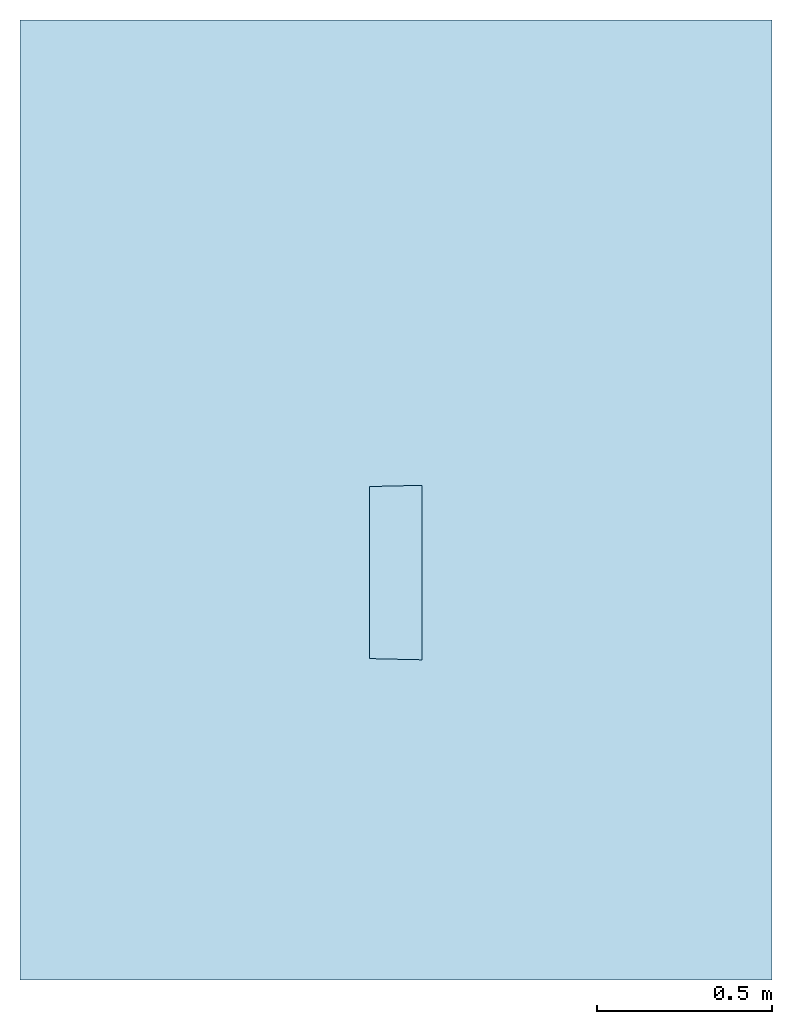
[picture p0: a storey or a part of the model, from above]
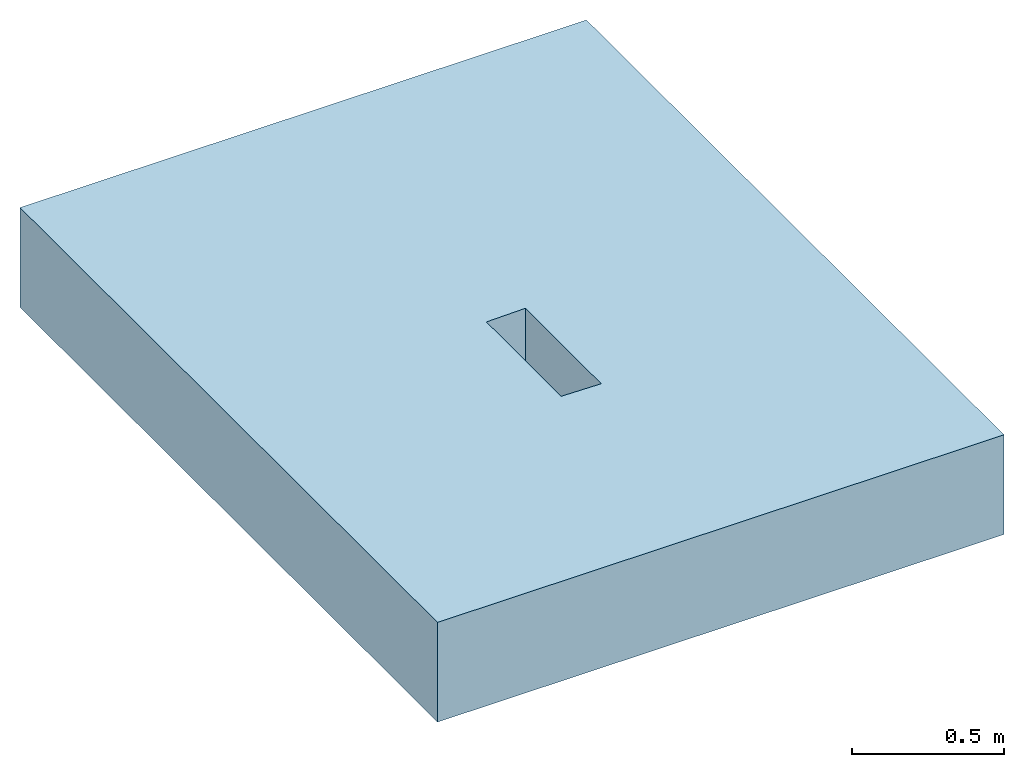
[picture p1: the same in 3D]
Properties of the parts of a building model (IFC2X3)

# File
Description: ViewDefinition [CoordinationView]
File name: 4936 - 25-11m external mitre.ifc
Time: 2013-09-18T16:24:00
Written by: Autodesk Revit 2013
Made in: 20120221_2030(x64)

# IfcProject, Project Number
LongName: Project Name; Phase: Project Status

# IfcSite, Default
RefLatitude: 42, 21, 30, 344238; RefLongitude: -71, -3, -35, -194702; RefElevation: 0 mm

# IfcBuilding
Pset_BuildingCommon - NumberOfStoreys: 2
Other - Project Name: Project Name; Client Name: Owner; Project Number: Project Number; Project Address: Enter address here; Project Status: Project Status; Project Issue Date: Issue Date

# IfcBuildingStorey (2)
Constraints - Elevation Base: 0
Graphics - Symbol at End 2 Default: yes; Color: 0; Line Weight: 1; Line Pattern: Center; Symbol at End 1 Default: no; Symbol: M_Level Head - Circle: M_Level Head - Circle
Identity Data - Structural: no; Building Story: yes
Dimensions - Computation Height: 0 mm
Name | LongName = Name | Elevation (mm) = Constraints, Elevation (mm)
T.O. Fnd. Wall | T.O. Fnd. Wall | -300
Level 1 | Level 1 | 0

# IfcBuildingElementProxy: 4936 - 25-11m external mitre, Civil-Drainage-Channel-ACO-KerbDrain-HB480(amar):4936 - 25-11m external mitre:4936 - 25-11m external mitre:481515
In: T.O. Fnd. Wall
Material: ACO Polymer Concrete.
Other - CreatedBy: www.aco.co.uk; Revision: 1
Identity Data - e-mail Technical: technical@aco.co.uk; URL: www.aco.co.uk; Product Code: 4936; Cost: 0; Fax: +44 (0)1462 815895; Price: POA - contact ACO; Telephone: +44 (0)1462 816666; Product Page URL: http://www.aco.co.uk/product_detail.php?id=3; Assembly Description: Rain Water Drainage; Installation guidelines: http://www.aco.co.uk/download.php?id=120; Type Comments: ACO KerbDrain HB480 half battered 25-11m external mitre unit 500/493mm long; e-mail Sales: customersupport@aco.co.uk; Product brochure: http://www.aco.co.uk/download.php?id=120; Model: ACO KerbDrain HB480; OmniClass Number: 23.70.50.24; Assembly Code: D2040; Model Description: Combined kerb and drainage system; Manufacturer: ACO Technologies plc - ACO Water Management Division; Maintenance guidelines: http://www.aco.co.uk/download.php?id=120; Address: ACO Business Park, Hitchin Road, Shefford, Bedfordshire, United Kingdom SG17 5TE; OmniClass Title: Rainwater Removal
Constraints - Level: Level: Level 1; Moves With Nearby Elements: no
Dimensions - Volume: 16561152 mm3; Void Depth: -6585 mm; Void Length: 500 mm; Mitre Small End: 492 mm; I/O endcap void depth: 2000 mm; Junction Start: 0 mm; Straight Void Start: -6580 mm; Void End I/O: 150 mm; Void Start I/O: 0 mm; Mitre Void End: 355 mm; Mitre Long end: 499 mm; Void Width: 150 mm; Junction End: 150 mm; junction void depth: 2000 mm; Mitre Void Start: 0 mm
Phasing - Phase Created: Phase 1
Pset_BuildingElementProxyCommon - Reference: 4936 - 25-11m external mitre
General - TagNumber: 0.000000; SerialNumber: 0.000000
Green Building Properties - End Cap Recyclable: N/A; Access Cover/Frame Recycled Material Content: N/A; Channel Recycled Material Content: 20% minimum; End Cap Recycled Material Content: N/A; Channel Recyclable: Fully recyclable; Access Cover/Frame Recyclable: N/A
Construction - Junction channel: no; 7-6m external mitre: no; LH drop kerb: no; LH BS transition kerb: no; 25-11m internal mitre: no; RH drop kerb: no; cable loop: no; KDHB480 500_blindunit: no; Junction access unit: no; RH BS transition kerb: no; Junction end cap: no; RH inlet/outlet end cap: no; 10-8m external mitre: no; Access Unit: no; LH inlet/outlet end cap: no; Centre Stone: no; Bus stop kerb: no; perforated centre stone: no; 25-11m external mitre: yes; Closing end cap: no; HB480-500: no
Data - Invert Depth: 455mm; Product Standard: BS EN 1433:2002, CE marked, Kitemarked; Concrete Surround Volume - Load Class A 15 - D 400 - Concrete Pavement: N/A; Load Class: A 15 - D 400; Hydraulic Performance: http://www.aco.co.uk/download.php?id=120; Channel C.S.A: 0.04m²; Installation - Concrete Grade: Refer to brochure; ACO Hydraulic Design Software: http://www.acodesign.co.uk; Drainage Slot Width: 50mm; Connection Pipe O.D: N/A; Concrete Surround Volume - Load Class A 15 - D 400 - Grass or Asphalt Pavement: N/A; Drainage Slot Intake area: 14592mm²/m; Product Weight: 35.2 Kg; Product Dimensions: 500/493mm x 150mm x 480mm (LxWxH)
Materials and Finishes - End Cap Colour: N/A; Channel Colour: Grey; Channel Material: Vienite® Synthetic Resin Concrete; Access Cover/Frame Finish: N/A; Access Cover/Frame Colour: N/A; Connection Pipe Material Colour: N/A; End Cap Material: N/A; Access Cover/Frame Material: N/A; Connection Pipe Material: N/A

# IfcOpeningElement: Opening (3)
In: Level 1
Constraints - Level: Level: Level 1; Height Offset From Level: 0 mm; Room Bounding: yes; Related to Mass: no
Dimensions - Volume: 2334314625 mm3; Perimeter: 9790 mm; Thickness: 400 mm; Area: 5901750 mm2
Structural - Enable Analytical Model: no; Structural: no
Phasing - Phase Created: Phase 1
Analytical Properties - Thermal Resistance (R): 0.477897; Absorptance: 0.1; Roughness: 1; Heat Transfer Coefficient (U): 2.0925; Thermal mass: 543920
Construction - Default Thickness: 400 mm; Function: 0
Graphics - Coarse Scale Fill Color: 0
Materials and Finishes - Structural Material: Earth

# IfcSlab: Floor:Generic Floor - 400mm, Floor:Generic Floor - 400mm:136426
In: Level 1
PredefinedType: FLOOR; Material: Earth 400 mm
Constraints - Level: Level: Level 1; Height Offset From Level: 0 mm; Room Bounding: yes; Related to Mass: no
Dimensions - Volume: 2334314625 mm3; Perimeter: 9790 mm; Thickness: 400 mm; Area: 5901750 mm2
Structural - Enable Analytical Model: no; Structural: no
Phasing - Phase Created: Phase 1
Pset_SlabCommon - Reference: Generic Floor - 400mm; IsExternal: no; LoadBearing: yes
Analytical Properties - Thermal Resistance (R): 0.477897; Absorptance: 0.1; Roughness: 1; Heat Transfer Coefficient (U): 2.0925; Thermal mass: 543920
Construction - Default Thickness: 400 mm; Function: 0
Graphics - Coarse Scale Fill Color: 0
Materials and Finishes - Structural Material: Earth
